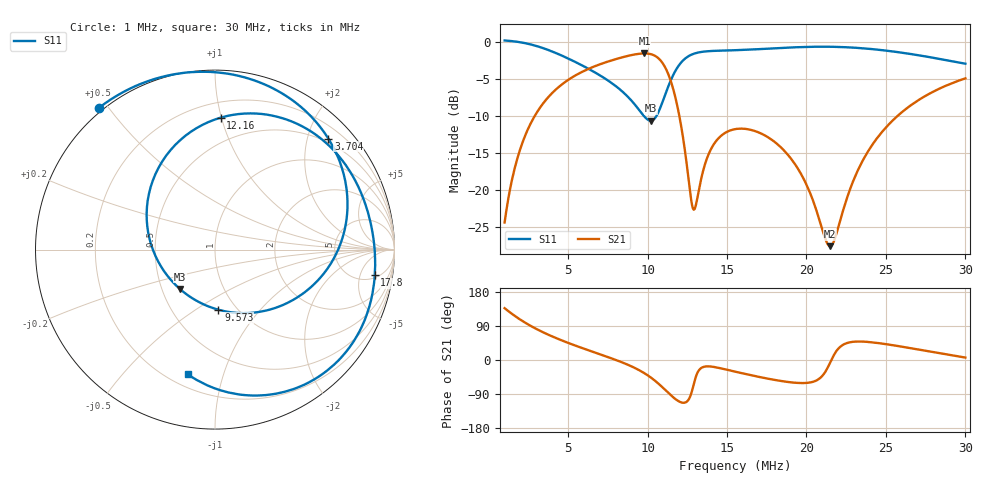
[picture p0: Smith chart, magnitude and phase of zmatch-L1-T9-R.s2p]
# HZ S RI R 50
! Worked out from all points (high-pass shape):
!   505 points, 1 MHz to 30 MHz, reference 50 ohm
!   highest |S21| = -1.57 dB at 9.804 MHz (marker M1); lowest = -27.5 dB at 21.48 MHz (marker M2)
!   |S21| within 3 dB of the highest: 5.422 MHz to 11.34 MHz (5.918 MHz wide, 70.6 % of centre)
!   lowest |S11| = -10.6 dB at 10.21 MHz (marker M3), VSWR 1.83, Z = 31 - j14.9 ohm
!   |S11| at or under -10 dB: 9.77 MHz to 10.55 MHz (783.7 kHz wide, 7.71 % of centre)
!   S12 and S22 are empty: the file has one direction only
!   S11 on the Smith chart (normalised r, x): 1 MHz: -0.01, +0.47; 3.704 MHz: 0.42, +2.39; 9.573 MHz: 0.83, -0.62; 12.16 MHz: 0.31, +0.99; 17.8 MHz: 6, -9; 30 MHz: 0.27, -0.77
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1000000  -0.6457 0.7903  -0.0443 0.0416  0 0  0 0
2150800  0.0382 0.9844  -0.0448 0.2085  0 0  0 0
2956360  0.4176 0.8419  0.0402 0.3222  0 0  0 0
3704380  0.6316 0.6185  0.1592 0.3873  0 0  0 0
4682560  0.7355 0.3146  0.3346 0.4029  0 0  0 0
5833360  0.6965 0.0256  0.5277 0.3328  0 0  0 0
8019880  0.4031 -0.2972  0.7653 -0.0028  0 0  0 0
9573460  0.0191 -0.3351  0.7256 -0.4078  0 0  0 0
9803620  -0.0568 -0.3081  0.6834 -0.4789  0 0  0 0
1.02064e7  -0.1948 -0.22  0.5692 -0.5969  0 0  0 0
1.066672e7  -0.3315 -0.0358  0.3666 -0.6847  0 0  0 0
1.13572e7  -0.3464 0.3851  0.0113 -0.5841  0 0  0 0
1.216276e7  0.0318 0.7354  -0.0956 -0.2323  0 0  0 0
1.291078e7  0.4208 0.7165  0.034 -0.0657  0 0  0 0
1.400404e7  0.7187 0.4847  0.1821 -0.0569  0 0  0 0
1.550008e7  0.8551 0.1964  0.222 -0.1315  0 0  0 0
1.780168e7  0.8902 -0.143  0.1378 -0.1707  0 0  0 0
2.033344e7  0.8009 -0.4631  0.047 -0.0764  0 0  0 0
2.148424e7  0.7158 -0.5867  0.0418 -0.00516  0 0  0 0
2.332552e7  0.5333 -0.7343  0.0942 0.1077  0 0  0 0
2.51668e7  0.3222 -0.8057  0.2096 0.1809  0 0  0 0
3.000016e7  -0.1506 -0.6957  0.5639 0.063  0 0  0 0
